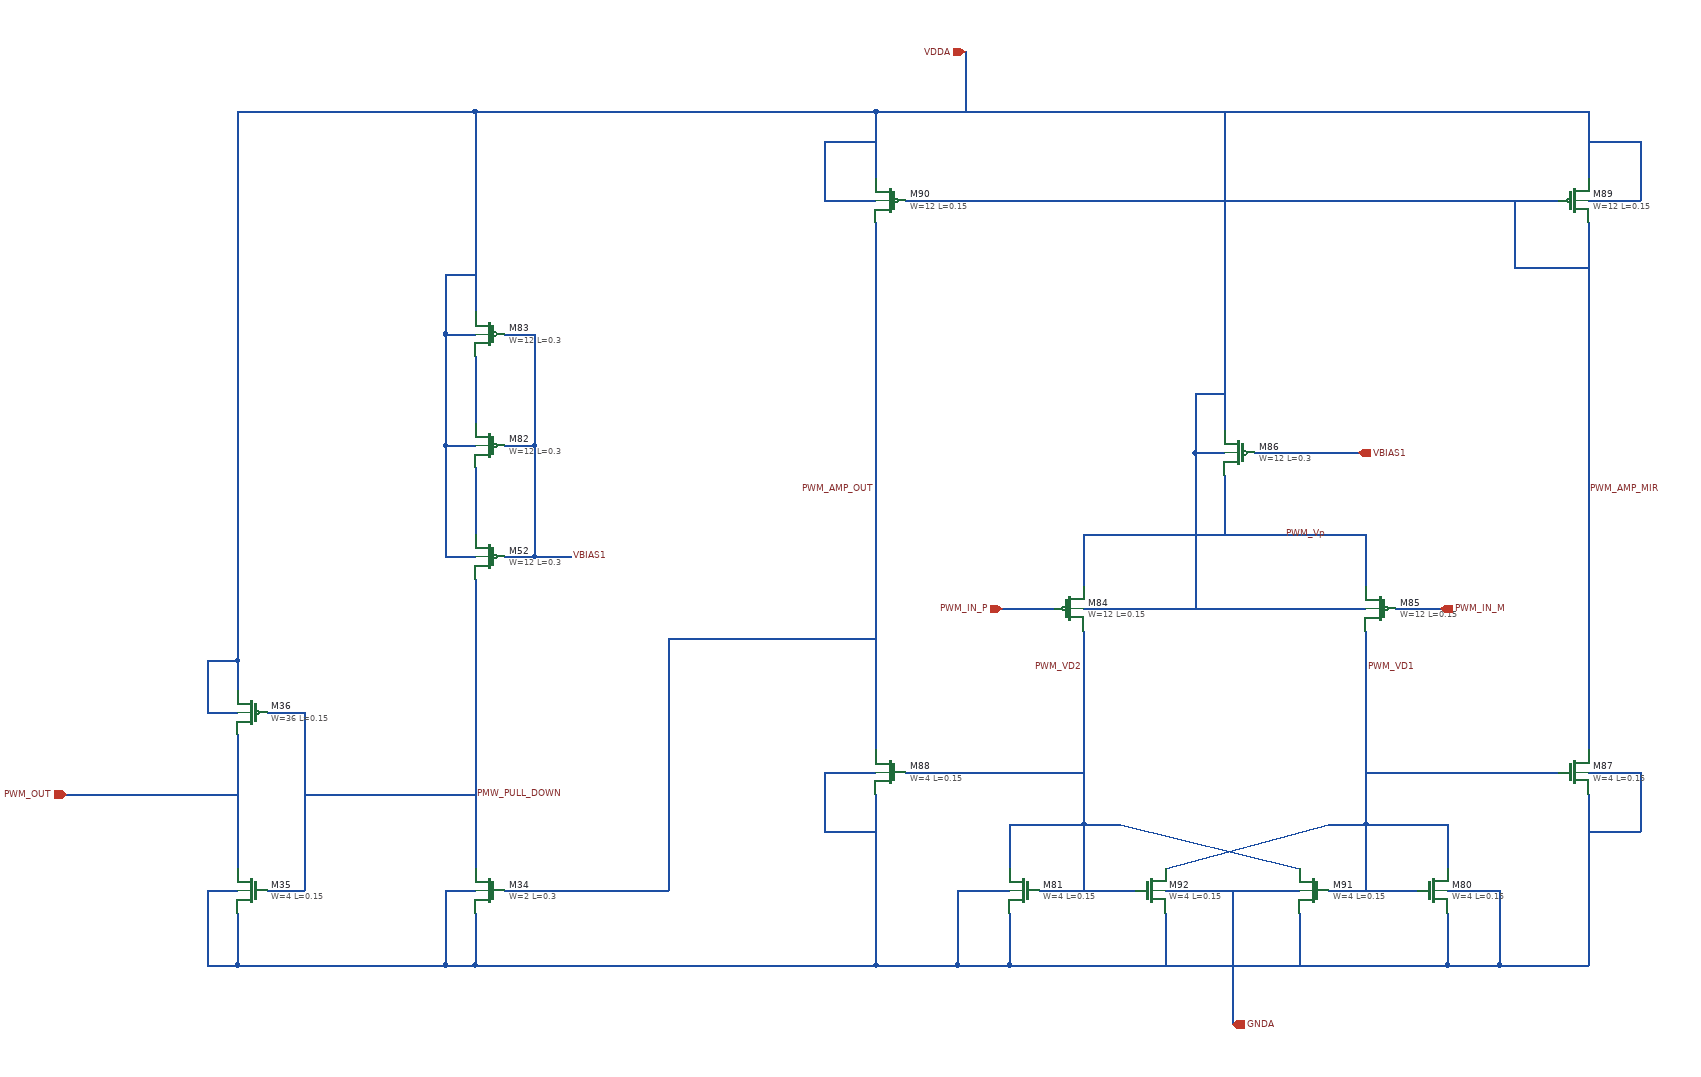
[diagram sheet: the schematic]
v {xschem version=3.4.6 file_version=1.2}
G {}
K {}
V {}
S {}
E {}
N 5980 -3920 5980 -3820 {lab=GNDA}
N 5980 -3820 6020 -3820 {lab=GNDA}
N 5980 -3920 6020 -3920 {lab=GNDA}
N 6020 -3890 6020 -3820 {lab=GNDA}
N 6020 -4340 6020 -3950 {lab=PMW_PULL_DOWN}
N 6100 -4370 6150 -4370 {lab=VBIAS_1}
N 5980 -4370 6020 -4370 {lab=VDDA}
N 6060 -4370 6100 -4370 {lab=VBIAS_1}
N 5980 -4450 5980 -4370 {lab=VDDA}
N 6020 -4490 6020 -4400 {lab=#net1}
N 5980 -4520 6020 -4520 {lab=VDDA}
N 6060 -4520 6100 -4520 {lab=VBIAS_1}
N 5980 -4600 5980 -4520 {lab=VDDA}
N 6020 -4640 6020 -4550 {lab=#net2}
N 5980 -4670 6020 -4670 {lab=VDDA}
N 6060 -4670 6100 -4670 {lab=VBIAS_1}
N 5980 -4750 6020 -4750 {lab=VDDA}
N 5980 -4750 5980 -4670 {lab=VDDA}
N 6020 -4790 6020 -4700 {lab=VDDA}
N 5980 -4670 5980 -4600 {lab=VDDA}
N 6100 -4670 6100 -4520 {lab=VBIAS_1}
N 5980 -4520 5980 -4450 {lab=VDDA}
N 6100 -4520 6100 -4370 {lab=VBIAS_1}
N 5660 -3920 5660 -3820 {lab=GNDA}
N 5660 -3820 5700 -3820 {lab=GNDA}
N 5660 -3920 5700 -3920 {lab=GNDA}
N 5700 -3890 5700 -3820 {lab=GNDA}
N 5790 -4000 5790 -3920 {lab=PMW_PULL_DOWN}
N 5740 -3920 5790 -3920 {lab=PMW_PULL_DOWN}
N 5700 -4130 5700 -3950 {lab=PWM_OUT}
N 5790 -4160 5790 -4000 {lab=PMW_PULL_DOWN}
N 5740 -4160 5790 -4160 {lab=PMW_PULL_DOWN}
N 5660 -4230 5660 -4160 {lab=VDDA}
N 5660 -4160 5700 -4160 {lab=VDDA}
N 5700 -4230 5700 -4190 {lab=VDDA}
N 5660 -4230 5700 -4230 {lab=VDDA}
N 5700 -4280 5700 -4230 {lab=VDDA}
N 5790 -4050 6020 -4050 {lab=PMW_PULL_DOWN}
N 5470 -4050 5700 -4050 {lab=PWM_OUT}
N 5700 -3820 5980 -3820 {lab=GNDA}
N 7220 -4400 7220 -4330 {lab=PWM_Vp}
N 6840 -4400 6840 -4330 {lab=PWM_Vp}
N 7220 -4270 7220 -4190 {lab=PWM_VD1}
N 6840 -4270 6840 -4190 {lab=PWM_VD2}
N 6740 -3820 7330 -3820 {lab=GNDA}
N 7040 -3820 7040 -3740 {lab=GNDA}
N 7260 -4300 7320 -4300 {lab=PWM_IN_M}
N 6730 -4300 6800 -4300 {lab=PWM_IN_P}
N 7400 -3920 7400 -3820 {lab=GNDA}
N 7330 -3820 7400 -3820 {lab=GNDA}
N 7330 -3920 7400 -3920 {lab=GNDA}
N 6670 -3920 6670 -3820 {lab=GNDA}
N 6670 -3820 6740 -3820 {lab=GNDA}
N 6670 -3920 6740 -3920 {lab=GNDA}
N 6840 -4300 7220 -4300 {lab=VDDA}
N 7330 -3890 7330 -3820 {lab=GNDA}
N 6740 -3890 6740 -3820 {lab=GNDA}
N 6840 -4400 7220 -4400 {lab=PWM_Vp}
N 7030 -4480 7030 -4400 {lab=PWM_Vp}
N 6990 -4510 7030 -4510 {lab=VDDA}
N 7070 -4510 7110 -4510 {lab=VBIAS1}
N 7110 -4510 7210 -4510 {lab=VBIAS1}
N 6990 -4510 6990 -4300 {lab=VDDA}
N 6990 -4590 7030 -4590 {lab=VDDA}
N 7030 -4630 7030 -4540 {lab=VDDA}
N 6990 -4590 6990 -4510 {lab=VDDA}
N 6950 -3920 7130 -3920 {lab=GNDA}
N 7170 -3920 7290 -3920 {lab=PWM_VD1}
N 6780 -3920 6910 -3920 {lab=PWM_VD2}
N 7220 -4010 7220 -3920 {lab=PWM_VD1}
N 7220 -4010 7330 -4010 {lab=PWM_VD1}
N 7330 -4010 7330 -3950 {lab=PWM_VD1}
N 7220 -4190 7220 -4010 {lab=PWM_VD1}
N 6840 -4010 6840 -3920 {lab=PWM_VD2}
N 6740 -4010 6840 -4010 {lab=PWM_VD2}
N 6740 -4010 6740 -3950 {lab=PWM_VD2}
N 7520 -4080 7590 -4080 {lab=GNDA}
N 7520 -4050 7520 -3820 {lab=GNDA}
N 7400 -3820 7520 -3820 {lab=GNDA}
N 7590 -4080 7590 -4000 {lab=GNDA}
N 7520 -4000 7590 -4000 {lab=GNDA}
N 6490 -4080 6560 -4080 {lab=GNDA}
N 6560 -4050 6560 -3820 {lab=GNDA}
N 6560 -3820 6670 -3820 {lab=GNDA}
N 6490 -4080 6490 -4000 {lab=GNDA}
N 6490 -4000 6560 -4000 {lab=GNDA}
N 6600 -4080 6840 -4080 {lab=PWM_VD2}
N 7220 -4080 7480 -4080 {lab=PWM_VD1}
N 7520 -4820 7520 -4110 {lab=PWM_AMP_MIR}
N 7520 -4970 7520 -4880 {lab=VDDA}
N 7520 -4850 7590 -4850 {lab=VDDA}
N 7590 -4930 7590 -4850 {lab=VDDA}
N 7520 -4930 7590 -4930 {lab=VDDA}
N 6560 -4820 6560 -4110 {lab=PWM_AMP_OUT}
N 6560 -4970 6560 -4880 {lab=VDDA}
N 6490 -4850 6560 -4850 {lab=VDDA}
N 6490 -4930 6490 -4850 {lab=VDDA}
N 6490 -4930 6560 -4930 {lab=VDDA}
N 6600 -4850 7480 -4850 {lab=PWM_AMP_MIR}
N 7420 -4850 7420 -4760 {lab=PWM_AMP_MIR}
N 7420 -4760 7520 -4760 {lab=PWM_AMP_MIR}
N 6950 -3890 6950 -3820 {lab=GNDA}
N 7130 -3890 7130 -3820 {lab=GNDA}
N 7040 -3920 7040 -3820 {lab=GNDA}
N 6840 -4190 6840 -4010 {lab=PWM_VD2}
N 6840 -4010 6890 -4010 {lab=PWM_VD2}
N 6890 -4010 7130 -3950 {lab=PWM_VD2}
N 6950 -3950 7170 -4010 {lab=PWM_VD1}
N 7170 -4010 7220 -4010 {lab=PWM_VD1}
N 6020 -3820 6560 -3820 {lab=GNDA}
N 6060 -3920 6280 -3920 {lab=PWM_AMP_OUT}
N 6280 -4260 6280 -3920 {lab=PWM_AMP_OUT}
N 6280 -4260 6560 -4260 {lab=PWM_AMP_OUT}
N 6560 -4970 7520 -4970 {lab=VDDA}
N 7030 -4970 7030 -4630 {lab=VDDA}
N 6020 -4970 6560 -4970 {lab=VDDA}
N 6020 -4970 6020 -4790 {lab=VDDA}
N 5700 -4970 5700 -4280 {lab=VDDA}
N 5700 -4970 6020 -4970 {lab=VDDA}
N 6680 -5050 6680 -4970 {lab=VDDA}
C {sky130_fd_pr/nfet_01v8.sym} 6040 -3920 0 1 {name=M34
W=2
L=0.3
nf=2 
mult=1
ad="'int((nf+1)/2) * W/nf * 0.29'" 
pd="'2*int((nf+1)/2) * (W/nf + 0.29)'"
as="'int((nf+2)/2) * W/nf * 0.29'" 
ps="'2*int((nf+2)/2) * (W/nf + 0.29)'"
nrd="'0.29 / W'" nrs="'0.29 / W'"
sa=0 sb=0 sd=0
model=nfet_01v8
spiceprefix=X
}
C {lab_wire.sym} 6150 -4370 0 1 {name=p31 sig_type=std_logic lab=VBIAS1}
C {sky130_fd_pr/pfet_01v8.sym} 6040 -4370 0 1 {name=M52
W=12
L=0.3
nf=1
mult=1
ad="'int((nf+1)/2) * W/nf * 0.29'" 
pd="'2*int((nf+1)/2) * (W/nf + 0.29)'"
as="'int((nf+2)/2) * W/nf * 0.29'" 
ps="'2*int((nf+2)/2) * (W/nf + 0.29)'"
nrd="'0.29 / W'" nrs="'0.29 / W'"
sa=0 sb=0 sd=0
model=pfet_01v8
spiceprefix=X
}
C {sky130_fd_pr/pfet_01v8.sym} 6040 -4520 0 1 {name=M82
W=12
L=0.3
nf=1
mult=1
ad="'int((nf+1)/2) * W/nf * 0.29'" 
pd="'2*int((nf+1)/2) * (W/nf + 0.29)'"
as="'int((nf+2)/2) * W/nf * 0.29'" 
ps="'2*int((nf+2)/2) * (W/nf + 0.29)'"
nrd="'0.29 / W'" nrs="'0.29 / W'"
sa=0 sb=0 sd=0
model=pfet_01v8
spiceprefix=X
}
C {sky130_fd_pr/pfet_01v8.sym} 6040 -4670 0 1 {name=M83
W=12
L=0.3
nf=1
mult=1
ad="'int((nf+1)/2) * W/nf * 0.29'" 
pd="'2*int((nf+1)/2) * (W/nf + 0.29)'"
as="'int((nf+2)/2) * W/nf * 0.29'" 
ps="'2*int((nf+2)/2) * (W/nf + 0.29)'"
nrd="'0.29 / W'" nrs="'0.29 / W'"
sa=0 sb=0 sd=0
model=pfet_01v8
spiceprefix=X
}
C {sky130_fd_pr/nfet_01v8.sym} 5720 -3920 0 1 {name=M35
W=4
L=0.15
nf=2 
mult=1
ad="'int((nf+1)/2) * W/nf * 0.29'" 
pd="'2*int((nf+1)/2) * (W/nf + 0.29)'"
as="'int((nf+2)/2) * W/nf * 0.29'" 
ps="'2*int((nf+2)/2) * (W/nf + 0.29)'"
nrd="'0.29 / W'" nrs="'0.29 / W'"
sa=0 sb=0 sd=0
model=nfet_01v8
spiceprefix=X
}
C {sky130_fd_pr/pfet_01v8.sym} 5720 -4160 0 1 {name=M36
W=36
L=0.15
nf=6
mult=1
ad="'int((nf+1)/2) * W/nf * 0.29'" 
pd="'2*int((nf+1)/2) * (W/nf + 0.29)'"
as="'int((nf+2)/2) * W/nf * 0.29'" 
ps="'2*int((nf+2)/2) * (W/nf + 0.29)'"
nrd="'0.29 / W'" nrs="'0.29 / W'"
sa=0 sb=0 sd=0
model=pfet_01v8
spiceprefix=X
}
C {lab_wire.sym} 6020 -4050 0 1 {name=p62 sig_type=std_logic lab=PMW_PULL_DOWN}
C {sky130_fd_pr/nfet_01v8.sym} 7310 -3920 0 0 {name=M80
W=4
L=0.15
nf=2 
mult=1
ad="'int((nf+1)/2) * W/nf * 0.29'" 
pd="'2*int((nf+1)/2) * (W/nf + 0.29)'"
as="'int((nf+2)/2) * W/nf * 0.29'" 
ps="'2*int((nf+2)/2) * (W/nf + 0.29)'"
nrd="'0.29 / W'" nrs="'0.29 / W'"
sa=0 sb=0 sd=0
model=nfet_01v8
spiceprefix=X
}
C {sky130_fd_pr/nfet_01v8.sym} 6760 -3920 0 1 {name=M81
W=4
L=0.15
nf=2 
mult=1
ad="'int((nf+1)/2) * W/nf * 0.29'" 
pd="'2*int((nf+1)/2) * (W/nf + 0.29)'"
as="'int((nf+2)/2) * W/nf * 0.29'" 
ps="'2*int((nf+2)/2) * (W/nf + 0.29)'"
nrd="'0.29 / W'" nrs="'0.29 / W'"
sa=0 sb=0 sd=0
model=nfet_01v8
spiceprefix=X
}
C {sky130_fd_pr/pfet_01v8.sym} 6820 -4300 0 0 {name=M84
W=12
L=0.15
nf=6
mult=1
ad="'int((nf+1)/2) * W/nf * 0.29'" 
pd="'2*int((nf+1)/2) * (W/nf + 0.29)'"
as="'int((nf+2)/2) * W/nf * 0.29'" 
ps="'2*int((nf+2)/2) * (W/nf + 0.29)'"
nrd="'0.29 / W'" nrs="'0.29 / W'"
sa=0 sb=0 sd=0
model=pfet_01v8
spiceprefix=X
}
C {sky130_fd_pr/pfet_01v8.sym} 7240 -4300 0 1 {name=M85
W=12
L=0.15
nf=6
mult=1
ad="'int((nf+1)/2) * W/nf * 0.29'" 
pd="'2*int((nf+1)/2) * (W/nf + 0.29)'"
as="'int((nf+2)/2) * W/nf * 0.29'" 
ps="'2*int((nf+2)/2) * (W/nf + 0.29)'"
nrd="'0.29 / W'" nrs="'0.29 / W'"
sa=0 sb=0 sd=0
model=pfet_01v8
spiceprefix=X
}
C {lab_pin.sym} 6560 -4460 0 0 {name=p73 lab=PWM_AMP_OUT}
C {lab_pin.sym} 7520 -4460 0 1 {name=p74 lab=PWM_AMP_MIR}
C {sky130_fd_pr/pfet_01v8.sym} 7050 -4510 0 1 {name=M86
W=12
L=0.3
nf=1
mult=1
ad="'int((nf+1)/2) * W/nf * 0.29'" 
pd="'2*int((nf+1)/2) * (W/nf + 0.29)'"
as="'int((nf+2)/2) * W/nf * 0.29'" 
ps="'2*int((nf+2)/2) * (W/nf + 0.29)'"
nrd="'0.29 / W'" nrs="'0.29 / W'"
sa=0 sb=0 sd=0
model=pfet_01v8
spiceprefix=X
}
C {lab_wire.sym} 7110 -4400 0 1 {name=p76 sig_type=std_logic lab=PWM_Vp}
C {lab_pin.sym} 6840 -4220 0 0 {name=p77 lab=PWM_VD2}
C {lab_pin.sym} 7220 -4220 0 1 {name=p78 lab=PWM_VD1}
C {sky130_fd_pr/nfet_01v8.sym} 7500 -4080 0 0 {name=M87
W=4
L=0.15
nf=2 
mult=1
ad="'int((nf+1)/2) * W/nf * 0.29'" 
pd="'2*int((nf+1)/2) * (W/nf + 0.29)'"
as="'int((nf+2)/2) * W/nf * 0.29'" 
ps="'2*int((nf+2)/2) * (W/nf + 0.29)'"
nrd="'0.29 / W'" nrs="'0.29 / W'"
sa=0 sb=0 sd=0
model=nfet_01v8
spiceprefix=X
}
C {sky130_fd_pr/nfet_01v8.sym} 6580 -4080 0 1 {name=M88
W=4
L=0.15
nf=2 
mult=1
ad="'int((nf+1)/2) * W/nf * 0.29'" 
pd="'2*int((nf+1)/2) * (W/nf + 0.29)'"
as="'int((nf+2)/2) * W/nf * 0.29'" 
ps="'2*int((nf+2)/2) * (W/nf + 0.29)'"
nrd="'0.29 / W'" nrs="'0.29 / W'"
sa=0 sb=0 sd=0
model=nfet_01v8
spiceprefix=X
}
C {sky130_fd_pr/pfet_01v8.sym} 7500 -4850 0 0 {name=M89
W=12
L=0.15
nf=6
mult=1
ad="'int((nf+1)/2) * W/nf * 0.29'" 
pd="'2*int((nf+1)/2) * (W/nf + 0.29)'"
as="'int((nf+2)/2) * W/nf * 0.29'" 
ps="'2*int((nf+2)/2) * (W/nf + 0.29)'"
nrd="'0.29 / W'" nrs="'0.29 / W'"
sa=0 sb=0 sd=0
model=pfet_01v8
spiceprefix=X
}
C {sky130_fd_pr/pfet_01v8.sym} 6580 -4850 0 1 {name=M90
W=12
L=0.15
nf=6
mult=1
ad="'int((nf+1)/2) * W/nf * 0.29'" 
pd="'2*int((nf+1)/2) * (W/nf + 0.29)'"
as="'int((nf+2)/2) * W/nf * 0.29'" 
ps="'2*int((nf+2)/2) * (W/nf + 0.29)'"
nrd="'0.29 / W'" nrs="'0.29 / W'"
sa=0 sb=0 sd=0
model=pfet_01v8
spiceprefix=X
}
C {sky130_fd_pr/nfet_01v8.sym} 7150 -3920 0 1 {name=M91
W=4
L=0.15
nf=2 
mult=1
ad="'int((nf+1)/2) * W/nf * 0.29'" 
pd="'2*int((nf+1)/2) * (W/nf + 0.29)'"
as="'int((nf+2)/2) * W/nf * 0.29'" 
ps="'2*int((nf+2)/2) * (W/nf + 0.29)'"
nrd="'0.29 / W'" nrs="'0.29 / W'"
sa=0 sb=0 sd=0
model=nfet_01v8
spiceprefix=X
}
C {sky130_fd_pr/nfet_01v8.sym} 6930 -3920 0 0 {name=M92
W=4
L=0.15
nf=2 
mult=1
ad="'int((nf+1)/2) * W/nf * 0.29'" 
pd="'2*int((nf+1)/2) * (W/nf + 0.29)'"
as="'int((nf+2)/2) * W/nf * 0.29'" 
ps="'2*int((nf+2)/2) * (W/nf + 0.29)'"
nrd="'0.29 / W'" nrs="'0.29 / W'"
sa=0 sb=0 sd=0
model=nfet_01v8
spiceprefix=X
}
C {iopin.sym} 7040 -3740 0 1 {name=p1 lab=GNDA}
C {iopin.sym} 6680 -5050 2 0 {name=p2 lab=VDDA}
C {ipin.sym} 6730 -4300 0 0 {name=p3 lab=PWM_IN_P}
C {opin.sym} 5470 -4050 0 1 {name=p4 lab=PWM_OUT}
C {ipin.sym} 7320 -4300 0 1 {name=p5 lab=PWM_IN_M}
C {ipin.sym} 7210 -4510 0 1 {name=p6 lab=VBIAS1}
